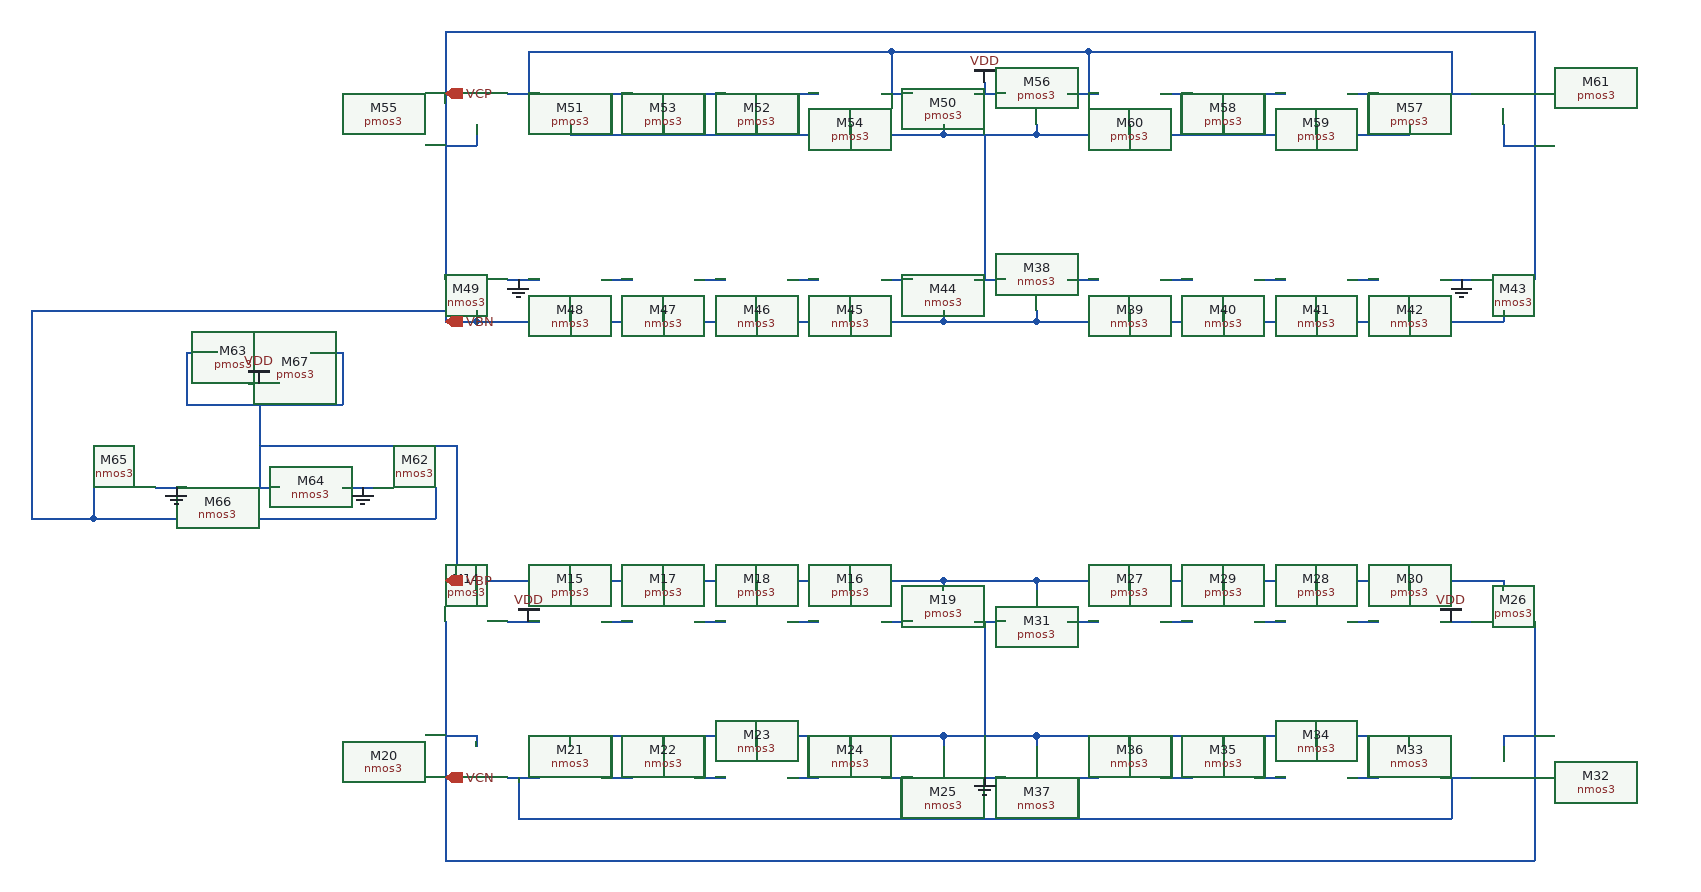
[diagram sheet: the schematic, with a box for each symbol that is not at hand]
v {xschem version=3.4.3 file_version=1.2
}
G {}
K {}
V {}
S {}
E {}
N 700 -140 730 -140 {
lab=VDD}
N 790 -140 820 -140 {
lab=#net1}
N 880 -140 910 -140 {
lab=#net2}
N 970 -140 1000 -140 {
lab=#net3}
N 1060 -140 1090 -140 {
lab=#net4}
N 760 -180 760 -170 {
lab=VBP}
N 850 -180 850 -170 {
lab=VBP}
N 940 -180 940 -170 {
lab=VBP}
N 670 -180 670 -170 {
lab=VBP}
N 1030 -180 1030 -170 {
lab=VBP}
N 1120 -180 1120 -170 {
lab=VBP}
N 640 -180 1120 -180 {
lab=VBP}
N 700 10 730 10 {
lab=#net5}
N 790 10 820 10 {
lab=#net6}
N 880 10 910 10 {
lab=#net6}
N 970 10 1000 10 {
lab=#net6}
N 1060 10 1090 10 {
lab=#net5}
N 670 -30 670 -20 {
lab=VCN}
N 760 -30 760 -20 {
lab=#net6}
N 850 -30 850 -20 {
lab=#net6}
N 940 -30 940 -20 {
lab=#net6}
N 1030 -30 1030 -20 {
lab=#net6}
N 1120 -30 1120 -20 {
lab=#net6}
N 760 -30 1120 -30 {
lab=#net6}
N 1600 -140 1630 -140 {
lab=VDD}
N 1510 -140 1540 -140 {
lab=#net7}
N 1420 -140 1450 -140 {
lab=#net8}
N 1330 -140 1360 -140 {
lab=#net9}
N 1240 -140 1270 -140 {
lab=#net10}
N 1570 -180 1570 -170 {
lab=VBP}
N 1480 -180 1480 -170 {
lab=VBP}
N 1390 -180 1390 -170 {
lab=VBP}
N 1660 -180 1660 -170 {
lab=VBP}
N 1300 -180 1300 -170 {
lab=VBP}
N 1210 -180 1210 -170 {
lab=VBP}
N 1600 10 1630 10 {
lab=#net5}
N 1510 10 1540 10 {
lab=#net6}
N 1420 10 1450 10 {
lab=#net6}
N 1330 10 1360 10 {
lab=#net6}
N 1240 10 1270 10 {
lab=#net5}
N 1660 -30 1660 -20 {
lab=VCN}
N 1570 -30 1570 -20 {
lab=#net6}
N 1480 -30 1480 -20 {
lab=#net6}
N 1390 -30 1390 -20 {
lab=#net6}
N 1300 -30 1300 -20 {
lab=#net6}
N 1210 -30 1210 -20 {
lab=#net6}
N 1210 -30 1570 -30 {
lab=#net6}
N 1150 10 1180 10 {
lab=GND}
N 1120 -30 1210 -30 {
lab=#net6}
N 1150 -140 1180 -140 {
lab=#net6}
N 640 -140 640 10 {
lab=VCN}
N 640 -30 670 -30 {
lab=VCN}
N 1690 -140 1690 10 {
lab=VCN}
N 1660 -30 1690 -30 {
lab=VCN}
N 1160 -140 1160 -30 {
lab=#net6}
N 710 10 710 50 {
lab=#net5}
N 710 50 900 50 {
lab=#net5}
N 900 50 1610 50 {
lab=#net5}
N 1610 10 1610 50 {
lab=#net5}
N 800 -30 800 10 {
lab=#net6}
N 890 -30 890 10 {
lab=#net6}
N 1080 10 1080 50 {
lab=#net5}
N 990 -30 990 10 {
lab=#net6}
N 1250 10 1250 50 {
lab=#net5}
N 1340 -30 1340 10 {
lab=#net6}
N 1430 -30 1430 10 {
lab=#net6}
N 1530 -30 1530 10 {
lab=#net6}
N 1210 -180 1660 -180 {
lab=VBP}
N 670 -440 670 -430 {
lab=VBN}
N 760 -440 760 -430 {
lab=VBN}
N 850 -440 850 -430 {
lab=VBN}
N 940 -440 940 -430 {
lab=VBN}
N 1030 -440 1030 -430 {
lab=VBN}
N 1120 -440 1120 -430 {
lab=VBN}
N 670 -430 1120 -430 {
lab=VBN}
N 700 -470 730 -470 {
lab=GND}
N 790 -470 820 -470 {
lab=#net11}
N 880 -470 910 -470 {
lab=#net12}
N 970 -470 1000 -470 {
lab=#net13}
N 1060 -470 1090 -470 {
lab=#net14}
N 700 -650 730 -650 {
lab=#net15}
N 790 -650 820 -650 {
lab=#net16}
N 880 -650 910 -650 {
lab=#net16}
N 970 -650 1000 -650 {
lab=#net16}
N 1060 -650 1090 -650 {
lab=#net15}
N 640 -650 640 -470 {
lab=VCP}
N 670 -620 670 -600 {
lab=VCP}
N 640 -600 670 -600 {
lab=VCP}
N 760 -620 760 -610 {
lab=#net16}
N 760 -610 1120 -610 {
lab=#net16}
N 1120 -620 1120 -610 {
lab=#net16}
N 800 -650 800 -610 {
lab=#net16}
N 720 -690 720 -650 {
lab=#net15}
N 720 -690 1070 -690 {
lab=#net15}
N 1070 -690 1070 -650 {
lab=#net15}
N 850 -620 850 -610 {
lab=#net16}
N 940 -620 940 -610 {
lab=#net16}
N 1030 -620 1030 -610 {
lab=#net16}
N 1160 -660 1160 -650 {
lab=VDD}
N 1660 -440 1660 -430 {
lab=VBN}
N 1570 -440 1570 -430 {
lab=VBN}
N 1480 -440 1480 -430 {
lab=VBN}
N 1390 -440 1390 -430 {
lab=VBN}
N 1300 -440 1300 -430 {
lab=VBN}
N 1210 -440 1210 -430 {
lab=VBN}
N 1210 -430 1660 -430 {
lab=VBN}
N 1600 -470 1630 -470 {
lab=GND}
N 1510 -470 1540 -470 {
lab=#net17}
N 1420 -470 1450 -470 {
lab=#net18}
N 1330 -470 1360 -470 {
lab=#net19}
N 1240 -470 1270 -470 {
lab=#net20}
N 1600 -650 1630 -650 {
lab=#net15}
N 1510 -650 1540 -650 {
lab=#net16}
N 1420 -650 1450 -650 {
lab=#net16}
N 1330 -650 1360 -650 {
lab=#net16}
N 1240 -650 1270 -650 {
lab=#net15}
N 1690 -650 1690 -470 {
lab=VCP}
N 1660 -620 1660 -600 {
lab=VCP}
N 1660 -600 1690 -600 {
lab=VCP}
N 1570 -620 1570 -610 {
lab=#net16}
N 1210 -610 1570 -610 {
lab=#net16}
N 1210 -620 1210 -610 {
lab=#net16}
N 1530 -650 1530 -610 {
lab=#net16}
N 1610 -690 1610 -650 {
lab=#net15}
N 1260 -690 1610 -690 {
lab=#net15}
N 1260 -690 1260 -650 {
lab=#net15}
N 1480 -620 1480 -610 {
lab=#net16}
N 1390 -620 1390 -610 {
lab=#net16}
N 1300 -620 1300 -610 {
lab=#net16}
N 1150 -650 1180 -650 {
lab=VDD}
N 1150 -470 1180 -470 {
lab=#net16}
N 1120 -610 1210 -610 {
lab=#net16}
N 1160 -610 1160 -470 {
lab=#net16}
N 1070 -690 1260 -690 {
lab=#net15}
N 1690 -710 1690 -650 {
lab=VCP}
N 640 -710 1690 -710 {
lab=VCP}
N 640 -710 640 -640 {
lab=VCP}
N 640 10 640 90 {
lab=VCN}
N 640 90 1690 90 {
lab=VCN}
N 1690 10 1690 90 {
lab=VCN}
N 640 -430 670 -430 {
lab=VBN}
N 630 -270 630 -240 {
lab=VBN}
N 510 -240 630 -240 {
lab=VBN}
N 540 -270 570 -270 {
lab=GND}
N 300 -270 300 -240 {
lab=VBN}
N 300 -240 420 -240 {
lab=VBN}
N 360 -270 390 -270 {
lab=GND}
N 450 -270 480 -270 {
lab=#net21}
N 420 -240 510 -240 {
lab=VBN}
N 450 -370 480 -370 {
lab=VDD}
N 390 -400 390 -370 {
lab=#net21}
N 390 -400 420 -400 {
lab=#net21}
N 510 -400 540 -400 {
lab=#net21}
N 540 -400 540 -370 {
lab=#net21}
N 390 -370 390 -350 {
lab=#net21}
N 390 -350 540 -350 {
lab=#net21}
N 540 -370 540 -350 {
lab=#net21}
N 460 -350 460 -270 {
lab=#net21}
N 1120 -430 1210 -430 {
lab=VBN}
N 1120 -180 1210 -180 {
lab=VBP}
N 890 -650 890 -610 {
lab=#net16}
N 980 -650 980 -610 {
lab=#net16}
N 1350 -650 1350 -610 {
lab=#net16}
N 1430 -650 1430 -610 {
lab=#net16}
N 460 -310 650 -310 {}
N 650 -310 650 -180 {}
N 240 -240 300 -240 {}
N 240 -440 240 -240 {}
N 240 -440 640 -440 {}
N 640 -440 640 -430 {}
C {madvlsi/pmos3.sym} 670 -140 1 0 {name=M14
L=0.5
W=12
body=VDD
nf=1
mult=1
ad="'int((nf+1)/2) * W/nf * 0.29'" 
pd="'2*int((nf+1)/2) * (W/nf + 0.29)'"
as="'int((nf+2)/2) * W/nf * 0.29'" 
ps="'2*int((nf+2)/2) * (W/nf + 0.29)'"
nrd="'0.29 / W'" nrs="'0.29 / W'"
sa=0 sb=0 sd=0
model=pfet_01v8
spiceprefix=X
}
C {madvlsi/pmos3.sym} 1030 -140 1 0 {name=M16
L=0.5
W=12
body=VDD
nf=1
mult=1
ad="'int((nf+1)/2) * W/nf * 0.29'" 
pd="'2*int((nf+1)/2) * (W/nf + 0.29)'"
as="'int((nf+2)/2) * W/nf * 0.29'" 
ps="'2*int((nf+2)/2) * (W/nf + 0.29)'"
nrd="'0.29 / W'" nrs="'0.29 / W'"
sa=0 sb=0 sd=0
model=pfet_01v8
spiceprefix=X
}
C {madvlsi/pmos3.sym} 850 -140 1 0 {name=M17
L=0.5
W=12
body=VDD
nf=1
mult=1
ad="'int((nf+1)/2) * W/nf * 0.29'" 
pd="'2*int((nf+1)/2) * (W/nf + 0.29)'"
as="'int((nf+2)/2) * W/nf * 0.29'" 
ps="'2*int((nf+2)/2) * (W/nf + 0.29)'"
nrd="'0.29 / W'" nrs="'0.29 / W'"
sa=0 sb=0 sd=0
model=pfet_01v8
spiceprefix=X
}
C {madvlsi/pmos3.sym} 940 -140 1 0 {name=M18
L=0.5
W=12
body=VDD
nf=1
mult=1
ad="'int((nf+1)/2) * W/nf * 0.29'" 
pd="'2*int((nf+1)/2) * (W/nf + 0.29)'"
as="'int((nf+2)/2) * W/nf * 0.29'" 
ps="'2*int((nf+2)/2) * (W/nf + 0.29)'"
nrd="'0.29 / W'" nrs="'0.29 / W'"
sa=0 sb=0 sd=0
model=pfet_01v8
spiceprefix=X
}
C {madvlsi/pmos3.sym} 760 -140 1 0 {name=M15
L=0.5
W=12
body=VDD
nf=1
mult=1
ad="'int((nf+1)/2) * W/nf * 0.29'" 
pd="'2*int((nf+1)/2) * (W/nf + 0.29)'"
as="'int((nf+2)/2) * W/nf * 0.29'" 
ps="'2*int((nf+2)/2) * (W/nf + 0.29)'"
nrd="'0.29 / W'" nrs="'0.29 / W'"
sa=0 sb=0 sd=0
model=pfet_01v8
spiceprefix=X
}
C {madvlsi/pmos3.sym} 1120 -140 1 0 {name=M19
L=0.5
W=12
body=VDD
nf=1
mult=1
ad="'int((nf+1)/2) * W/nf * 0.29'" 
pd="'2*int((nf+1)/2) * (W/nf + 0.29)'"
as="'int((nf+2)/2) * W/nf * 0.29'" 
ps="'2*int((nf+2)/2) * (W/nf + 0.29)'"
nrd="'0.29 / W'" nrs="'0.29 / W'"
sa=0 sb=0 sd=0
model=pfet_01v8
spiceprefix=X
}
C {madvlsi/vdd.sym} 720 -140 0 0 {name=l4 lab=VDD}
C {madvlsi/nmos3.sym} 670 10 3 1 {name=M20
L=0.5
W=12
body=GND
nf=1
mult=1
ad="'int((nf+1)/2) * W/nf * 0.29'" 
pd="'2*int((nf+1)/2) * (W/nf + 0.29)'"
as="'int((nf+2)/2) * W/nf * 0.29'" 
ps="'2*int((nf+2)/2) * (W/nf + 0.29)'"
nrd="'0.29 / W'" nrs="'0.29 / W'"
sa=0 sb=0 sd=0
model=nfet_01v8
spiceprefix=X
}
C {madvlsi/nmos3.sym} 760 10 3 1 {name=M21
L=0.5
W=12
body=GND
nf=1
mult=1
ad="'int((nf+1)/2) * W/nf * 0.29'" 
pd="'2*int((nf+1)/2) * (W/nf + 0.29)'"
as="'int((nf+2)/2) * W/nf * 0.29'" 
ps="'2*int((nf+2)/2) * (W/nf + 0.29)'"
nrd="'0.29 / W'" nrs="'0.29 / W'"
sa=0 sb=0 sd=0
model=nfet_01v8
spiceprefix=X
}
C {madvlsi/nmos3.sym} 850 10 3 1 {name=M22
L=0.5
W=12
body=GND
nf=1
mult=1
ad="'int((nf+1)/2) * W/nf * 0.29'" 
pd="'2*int((nf+1)/2) * (W/nf + 0.29)'"
as="'int((nf+2)/2) * W/nf * 0.29'" 
ps="'2*int((nf+2)/2) * (W/nf + 0.29)'"
nrd="'0.29 / W'" nrs="'0.29 / W'"
sa=0 sb=0 sd=0
model=nfet_01v8
spiceprefix=X
}
C {madvlsi/nmos3.sym} 940 10 3 1 {name=M23
L=0.5
W=12
body=GND
nf=1
mult=1
ad="'int((nf+1)/2) * W/nf * 0.29'" 
pd="'2*int((nf+1)/2) * (W/nf + 0.29)'"
as="'int((nf+2)/2) * W/nf * 0.29'" 
ps="'2*int((nf+2)/2) * (W/nf + 0.29)'"
nrd="'0.29 / W'" nrs="'0.29 / W'"
sa=0 sb=0 sd=0
model=nfet_01v8
spiceprefix=X
}
C {madvlsi/nmos3.sym} 1030 10 3 1 {name=M24
L=0.5
W=12
body=GND
nf=1
mult=1
ad="'int((nf+1)/2) * W/nf * 0.29'" 
pd="'2*int((nf+1)/2) * (W/nf + 0.29)'"
as="'int((nf+2)/2) * W/nf * 0.29'" 
ps="'2*int((nf+2)/2) * (W/nf + 0.29)'"
nrd="'0.29 / W'" nrs="'0.29 / W'"
sa=0 sb=0 sd=0
model=nfet_01v8
spiceprefix=X
}
C {madvlsi/nmos3.sym} 1120 10 3 1 {name=M25
L=0.5
W=12
body=GND
nf=1
mult=1
ad="'int((nf+1)/2) * W/nf * 0.29'" 
pd="'2*int((nf+1)/2) * (W/nf + 0.29)'"
as="'int((nf+2)/2) * W/nf * 0.29'" 
ps="'2*int((nf+2)/2) * (W/nf + 0.29)'"
nrd="'0.29 / W'" nrs="'0.29 / W'"
sa=0 sb=0 sd=0
model=nfet_01v8
spiceprefix=X
}
C {madvlsi/pmos3.sym} 1660 -140 3 1 {name=M26
L=0.5
W=12
body=VDD
nf=1
mult=1
ad="'int((nf+1)/2) * W/nf * 0.29'" 
pd="'2*int((nf+1)/2) * (W/nf + 0.29)'"
as="'int((nf+2)/2) * W/nf * 0.29'" 
ps="'2*int((nf+2)/2) * (W/nf + 0.29)'"
nrd="'0.29 / W'" nrs="'0.29 / W'"
sa=0 sb=0 sd=0
model=pfet_01v8
spiceprefix=X
}
C {madvlsi/pmos3.sym} 1300 -140 3 1 {name=M27
L=0.5
W=12
body=VDD
nf=1
mult=1
ad="'int((nf+1)/2) * W/nf * 0.29'" 
pd="'2*int((nf+1)/2) * (W/nf + 0.29)'"
as="'int((nf+2)/2) * W/nf * 0.29'" 
ps="'2*int((nf+2)/2) * (W/nf + 0.29)'"
nrd="'0.29 / W'" nrs="'0.29 / W'"
sa=0 sb=0 sd=0
model=pfet_01v8
spiceprefix=X
}
C {madvlsi/pmos3.sym} 1480 -140 3 1 {name=M28
L=0.5
W=12
body=VDD
nf=1
mult=1
ad="'int((nf+1)/2) * W/nf * 0.29'" 
pd="'2*int((nf+1)/2) * (W/nf + 0.29)'"
as="'int((nf+2)/2) * W/nf * 0.29'" 
ps="'2*int((nf+2)/2) * (W/nf + 0.29)'"
nrd="'0.29 / W'" nrs="'0.29 / W'"
sa=0 sb=0 sd=0
model=pfet_01v8
spiceprefix=X
}
C {madvlsi/pmos3.sym} 1390 -140 3 1 {name=M29
L=0.5
W=12
body=VDD
nf=1
mult=1
ad="'int((nf+1)/2) * W/nf * 0.29'" 
pd="'2*int((nf+1)/2) * (W/nf + 0.29)'"
as="'int((nf+2)/2) * W/nf * 0.29'" 
ps="'2*int((nf+2)/2) * (W/nf + 0.29)'"
nrd="'0.29 / W'" nrs="'0.29 / W'"
sa=0 sb=0 sd=0
model=pfet_01v8
spiceprefix=X
}
C {madvlsi/pmos3.sym} 1570 -140 3 1 {name=M30
L=0.5
W=12
body=VDD
nf=1
mult=1
ad="'int((nf+1)/2) * W/nf * 0.29'" 
pd="'2*int((nf+1)/2) * (W/nf + 0.29)'"
as="'int((nf+2)/2) * W/nf * 0.29'" 
ps="'2*int((nf+2)/2) * (W/nf + 0.29)'"
nrd="'0.29 / W'" nrs="'0.29 / W'"
sa=0 sb=0 sd=0
model=pfet_01v8
spiceprefix=X
}
C {madvlsi/pmos3.sym} 1210 -140 3 1 {name=M31
L=0.5
W=12
body=VDD
nf=1
mult=1
ad="'int((nf+1)/2) * W/nf * 0.29'" 
pd="'2*int((nf+1)/2) * (W/nf + 0.29)'"
as="'int((nf+2)/2) * W/nf * 0.29'" 
ps="'2*int((nf+2)/2) * (W/nf + 0.29)'"
nrd="'0.29 / W'" nrs="'0.29 / W'"
sa=0 sb=0 sd=0
model=pfet_01v8
spiceprefix=X
}
C {madvlsi/vdd.sym} 1610 -140 0 1 {name=l5 lab=VDD}
C {madvlsi/nmos3.sym} 1660 10 1 0 {name=M32
L=0.5
W=12
body=GND
nf=1
mult=1
ad="'int((nf+1)/2) * W/nf * 0.29'" 
pd="'2*int((nf+1)/2) * (W/nf + 0.29)'"
as="'int((nf+2)/2) * W/nf * 0.29'" 
ps="'2*int((nf+2)/2) * (W/nf + 0.29)'"
nrd="'0.29 / W'" nrs="'0.29 / W'"
sa=0 sb=0 sd=0
model=nfet_01v8
spiceprefix=X
}
C {madvlsi/nmos3.sym} 1570 10 1 0 {name=M33
L=0.5
W=12
body=GND
nf=1
mult=1
ad="'int((nf+1)/2) * W/nf * 0.29'" 
pd="'2*int((nf+1)/2) * (W/nf + 0.29)'"
as="'int((nf+2)/2) * W/nf * 0.29'" 
ps="'2*int((nf+2)/2) * (W/nf + 0.29)'"
nrd="'0.29 / W'" nrs="'0.29 / W'"
sa=0 sb=0 sd=0
model=nfet_01v8
spiceprefix=X
}
C {madvlsi/nmos3.sym} 1480 10 1 0 {name=M34
L=0.5
W=12
body=GND
nf=1
mult=1
ad="'int((nf+1)/2) * W/nf * 0.29'" 
pd="'2*int((nf+1)/2) * (W/nf + 0.29)'"
as="'int((nf+2)/2) * W/nf * 0.29'" 
ps="'2*int((nf+2)/2) * (W/nf + 0.29)'"
nrd="'0.29 / W'" nrs="'0.29 / W'"
sa=0 sb=0 sd=0
model=nfet_01v8
spiceprefix=X
}
C {madvlsi/nmos3.sym} 1390 10 1 0 {name=M35
L=0.5
W=12
body=GND
nf=1
mult=1
ad="'int((nf+1)/2) * W/nf * 0.29'" 
pd="'2*int((nf+1)/2) * (W/nf + 0.29)'"
as="'int((nf+2)/2) * W/nf * 0.29'" 
ps="'2*int((nf+2)/2) * (W/nf + 0.29)'"
nrd="'0.29 / W'" nrs="'0.29 / W'"
sa=0 sb=0 sd=0
model=nfet_01v8
spiceprefix=X
}
C {madvlsi/nmos3.sym} 1300 10 1 0 {name=M36
L=0.5
W=12
body=GND
nf=1
mult=1
ad="'int((nf+1)/2) * W/nf * 0.29'" 
pd="'2*int((nf+1)/2) * (W/nf + 0.29)'"
as="'int((nf+2)/2) * W/nf * 0.29'" 
ps="'2*int((nf+2)/2) * (W/nf + 0.29)'"
nrd="'0.29 / W'" nrs="'0.29 / W'"
sa=0 sb=0 sd=0
model=nfet_01v8
spiceprefix=X
}
C {madvlsi/nmos3.sym} 1210 10 1 0 {name=M37
L=0.5
W=12
body=GND
nf=1
mult=1
ad="'int((nf+1)/2) * W/nf * 0.29'" 
pd="'2*int((nf+1)/2) * (W/nf + 0.29)'"
as="'int((nf+2)/2) * W/nf * 0.29'" 
ps="'2*int((nf+2)/2) * (W/nf + 0.29)'"
nrd="'0.29 / W'" nrs="'0.29 / W'"
sa=0 sb=0 sd=0
model=nfet_01v8
spiceprefix=X
}
C {devices/opin.sym} 640 -180 2 0 {name=p2 lab=VBP}
C {devices/opin.sym} 640 10 2 0 {name=p6 lab=VCN}
C {madvlsi/gnd.sym} 1160 10 0 0 {name=l6 lab=GND}
C {madvlsi/nmos3.sym} 1120 -470 3 0 {name=M44
L=0.5
W=12
body=GND
nf=1
mult=1
ad="'int((nf+1)/2) * W/nf * 0.29'" 
pd="'2*int((nf+1)/2) * (W/nf + 0.29)'"
as="'int((nf+2)/2) * W/nf * 0.29'" 
ps="'2*int((nf+2)/2) * (W/nf + 0.29)'"
nrd="'0.29 / W'" nrs="'0.29 / W'"
sa=0 sb=0 sd=0
model=nfet_01v8
spiceprefix=X
}
C {madvlsi/nmos3.sym} 1030 -470 3 0 {name=M45
L=0.5
W=12
body=GND
nf=1
mult=1
ad="'int((nf+1)/2) * W/nf * 0.29'" 
pd="'2*int((nf+1)/2) * (W/nf + 0.29)'"
as="'int((nf+2)/2) * W/nf * 0.29'" 
ps="'2*int((nf+2)/2) * (W/nf + 0.29)'"
nrd="'0.29 / W'" nrs="'0.29 / W'"
sa=0 sb=0 sd=0
model=nfet_01v8
spiceprefix=X
}
C {madvlsi/nmos3.sym} 940 -470 3 0 {name=M46
L=0.5
W=12
body=GND
nf=1
mult=1
ad="'int((nf+1)/2) * W/nf * 0.29'" 
pd="'2*int((nf+1)/2) * (W/nf + 0.29)'"
as="'int((nf+2)/2) * W/nf * 0.29'" 
ps="'2*int((nf+2)/2) * (W/nf + 0.29)'"
nrd="'0.29 / W'" nrs="'0.29 / W'"
sa=0 sb=0 sd=0
model=nfet_01v8
spiceprefix=X
}
C {madvlsi/nmos3.sym} 850 -470 3 0 {name=M47
L=0.5
W=12
body=GND
nf=1
mult=1
ad="'int((nf+1)/2) * W/nf * 0.29'" 
pd="'2*int((nf+1)/2) * (W/nf + 0.29)'"
as="'int((nf+2)/2) * W/nf * 0.29'" 
ps="'2*int((nf+2)/2) * (W/nf + 0.29)'"
nrd="'0.29 / W'" nrs="'0.29 / W'"
sa=0 sb=0 sd=0
model=nfet_01v8
spiceprefix=X
}
C {madvlsi/nmos3.sym} 760 -470 3 0 {name=M48
L=0.5
W=12
body=GND
nf=1
mult=1
ad="'int((nf+1)/2) * W/nf * 0.29'" 
pd="'2*int((nf+1)/2) * (W/nf + 0.29)'"
as="'int((nf+2)/2) * W/nf * 0.29'" 
ps="'2*int((nf+2)/2) * (W/nf + 0.29)'"
nrd="'0.29 / W'" nrs="'0.29 / W'"
sa=0 sb=0 sd=0
model=nfet_01v8
spiceprefix=X
}
C {madvlsi/nmos3.sym} 670 -470 3 0 {name=M49
L=0.5
W=12
body=GND
nf=1
mult=1
ad="'int((nf+1)/2) * W/nf * 0.29'" 
pd="'2*int((nf+1)/2) * (W/nf + 0.29)'"
as="'int((nf+2)/2) * W/nf * 0.29'" 
ps="'2*int((nf+2)/2) * (W/nf + 0.29)'"
nrd="'0.29 / W'" nrs="'0.29 / W'"
sa=0 sb=0 sd=0
model=nfet_01v8
spiceprefix=X
}
C {madvlsi/pmos3.sym} 1120 -650 3 0 {name=M50
L=0.5
W=12
body=VDD
nf=1
mult=1
ad="'int((nf+1)/2) * W/nf * 0.29'" 
pd="'2*int((nf+1)/2) * (W/nf + 0.29)'"
as="'int((nf+2)/2) * W/nf * 0.29'" 
ps="'2*int((nf+2)/2) * (W/nf + 0.29)'"
nrd="'0.29 / W'" nrs="'0.29 / W'"
sa=0 sb=0 sd=0
model=pfet_01v8
spiceprefix=X
}
C {madvlsi/pmos3.sym} 760 -650 3 0 {name=M51
L=0.5
W=12
body=VDD
nf=1
mult=1
ad="'int((nf+1)/2) * W/nf * 0.29'" 
pd="'2*int((nf+1)/2) * (W/nf + 0.29)'"
as="'int((nf+2)/2) * W/nf * 0.29'" 
ps="'2*int((nf+2)/2) * (W/nf + 0.29)'"
nrd="'0.29 / W'" nrs="'0.29 / W'"
sa=0 sb=0 sd=0
model=pfet_01v8
spiceprefix=X
}
C {madvlsi/pmos3.sym} 940 -650 3 0 {name=M52
L=0.5
W=12
body=VDD
nf=1
mult=1
ad="'int((nf+1)/2) * W/nf * 0.29'" 
pd="'2*int((nf+1)/2) * (W/nf + 0.29)'"
as="'int((nf+2)/2) * W/nf * 0.29'" 
ps="'2*int((nf+2)/2) * (W/nf + 0.29)'"
nrd="'0.29 / W'" nrs="'0.29 / W'"
sa=0 sb=0 sd=0
model=pfet_01v8
spiceprefix=X
}
C {madvlsi/pmos3.sym} 850 -650 3 0 {name=M53
L=0.5
W=12
body=VDD
nf=1
mult=1
ad="'int((nf+1)/2) * W/nf * 0.29'" 
pd="'2*int((nf+1)/2) * (W/nf + 0.29)'"
as="'int((nf+2)/2) * W/nf * 0.29'" 
ps="'2*int((nf+2)/2) * (W/nf + 0.29)'"
nrd="'0.29 / W'" nrs="'0.29 / W'"
sa=0 sb=0 sd=0
model=pfet_01v8
spiceprefix=X
}
C {madvlsi/pmos3.sym} 1030 -650 3 0 {name=M54
L=0.5
W=12
body=VDD
nf=1
mult=1
ad="'int((nf+1)/2) * W/nf * 0.29'" 
pd="'2*int((nf+1)/2) * (W/nf + 0.29)'"
as="'int((nf+2)/2) * W/nf * 0.29'" 
ps="'2*int((nf+2)/2) * (W/nf + 0.29)'"
nrd="'0.29 / W'" nrs="'0.29 / W'"
sa=0 sb=0 sd=0
model=pfet_01v8
spiceprefix=X
}
C {madvlsi/pmos3.sym} 670 -650 3 0 {name=M55
L=0.5
W=12
body=VDD
nf=1
mult=1
ad="'int((nf+1)/2) * W/nf * 0.29'" 
pd="'2*int((nf+1)/2) * (W/nf + 0.29)'"
as="'int((nf+2)/2) * W/nf * 0.29'" 
ps="'2*int((nf+2)/2) * (W/nf + 0.29)'"
nrd="'0.29 / W'" nrs="'0.29 / W'"
sa=0 sb=0 sd=0
model=pfet_01v8
spiceprefix=X
}
C {madvlsi/gnd.sym} 710 -470 0 0 {name=l8 lab=GND}
C {madvlsi/vdd.sym} 1160 -660 0 1 {name=l9 lab=VDD}
C {madvlsi/nmos3.sym} 1210 -470 1 1 {name=M38
L=0.5
W=12
body=GND
nf=1
mult=1
ad="'int((nf+1)/2) * W/nf * 0.29'" 
pd="'2*int((nf+1)/2) * (W/nf + 0.29)'"
as="'int((nf+2)/2) * W/nf * 0.29'" 
ps="'2*int((nf+2)/2) * (W/nf + 0.29)'"
nrd="'0.29 / W'" nrs="'0.29 / W'"
sa=0 sb=0 sd=0
model=nfet_01v8
spiceprefix=X
}
C {madvlsi/nmos3.sym} 1300 -470 1 1 {name=M39
L=0.5
W=12
body=GND
nf=1
mult=1
ad="'int((nf+1)/2) * W/nf * 0.29'" 
pd="'2*int((nf+1)/2) * (W/nf + 0.29)'"
as="'int((nf+2)/2) * W/nf * 0.29'" 
ps="'2*int((nf+2)/2) * (W/nf + 0.29)'"
nrd="'0.29 / W'" nrs="'0.29 / W'"
sa=0 sb=0 sd=0
model=nfet_01v8
spiceprefix=X
}
C {madvlsi/nmos3.sym} 1390 -470 1 1 {name=M40
L=0.5
W=12
body=GND
nf=1
mult=1
ad="'int((nf+1)/2) * W/nf * 0.29'" 
pd="'2*int((nf+1)/2) * (W/nf + 0.29)'"
as="'int((nf+2)/2) * W/nf * 0.29'" 
ps="'2*int((nf+2)/2) * (W/nf + 0.29)'"
nrd="'0.29 / W'" nrs="'0.29 / W'"
sa=0 sb=0 sd=0
model=nfet_01v8
spiceprefix=X
}
C {madvlsi/nmos3.sym} 1480 -470 1 1 {name=M41
L=0.5
W=12
body=GND
nf=1
mult=1
ad="'int((nf+1)/2) * W/nf * 0.29'" 
pd="'2*int((nf+1)/2) * (W/nf + 0.29)'"
as="'int((nf+2)/2) * W/nf * 0.29'" 
ps="'2*int((nf+2)/2) * (W/nf + 0.29)'"
nrd="'0.29 / W'" nrs="'0.29 / W'"
sa=0 sb=0 sd=0
model=nfet_01v8
spiceprefix=X
}
C {madvlsi/nmos3.sym} 1570 -470 1 1 {name=M42
L=0.5
W=12
body=GND
nf=1
mult=1
ad="'int((nf+1)/2) * W/nf * 0.29'" 
pd="'2*int((nf+1)/2) * (W/nf + 0.29)'"
as="'int((nf+2)/2) * W/nf * 0.29'" 
ps="'2*int((nf+2)/2) * (W/nf + 0.29)'"
nrd="'0.29 / W'" nrs="'0.29 / W'"
sa=0 sb=0 sd=0
model=nfet_01v8
spiceprefix=X
}
C {madvlsi/nmos3.sym} 1660 -470 1 1 {name=M43
L=0.5
W=12
body=GND
nf=1
mult=1
ad="'int((nf+1)/2) * W/nf * 0.29'" 
pd="'2*int((nf+1)/2) * (W/nf + 0.29)'"
as="'int((nf+2)/2) * W/nf * 0.29'" 
ps="'2*int((nf+2)/2) * (W/nf + 0.29)'"
nrd="'0.29 / W'" nrs="'0.29 / W'"
sa=0 sb=0 sd=0
model=nfet_01v8
spiceprefix=X
}
C {madvlsi/pmos3.sym} 1210 -650 1 1 {name=M56
L=0.5
W=12
body=VDD
nf=1
mult=1
ad="'int((nf+1)/2) * W/nf * 0.29'" 
pd="'2*int((nf+1)/2) * (W/nf + 0.29)'"
as="'int((nf+2)/2) * W/nf * 0.29'" 
ps="'2*int((nf+2)/2) * (W/nf + 0.29)'"
nrd="'0.29 / W'" nrs="'0.29 / W'"
sa=0 sb=0 sd=0
model=pfet_01v8
spiceprefix=X
}
C {madvlsi/pmos3.sym} 1570 -650 1 1 {name=M57
L=0.5
W=12
body=VDD
nf=1
mult=1
ad="'int((nf+1)/2) * W/nf * 0.29'" 
pd="'2*int((nf+1)/2) * (W/nf + 0.29)'"
as="'int((nf+2)/2) * W/nf * 0.29'" 
ps="'2*int((nf+2)/2) * (W/nf + 0.29)'"
nrd="'0.29 / W'" nrs="'0.29 / W'"
sa=0 sb=0 sd=0
model=pfet_01v8
spiceprefix=X
}
C {madvlsi/pmos3.sym} 1390 -650 1 1 {name=M58
L=0.5
W=12
body=VDD
nf=1
mult=1
ad="'int((nf+1)/2) * W/nf * 0.29'" 
pd="'2*int((nf+1)/2) * (W/nf + 0.29)'"
as="'int((nf+2)/2) * W/nf * 0.29'" 
ps="'2*int((nf+2)/2) * (W/nf + 0.29)'"
nrd="'0.29 / W'" nrs="'0.29 / W'"
sa=0 sb=0 sd=0
model=pfet_01v8
spiceprefix=X
}
C {madvlsi/pmos3.sym} 1480 -650 1 1 {name=M59
L=0.5
W=12
body=VDD
nf=1
mult=1
ad="'int((nf+1)/2) * W/nf * 0.29'" 
pd="'2*int((nf+1)/2) * (W/nf + 0.29)'"
as="'int((nf+2)/2) * W/nf * 0.29'" 
ps="'2*int((nf+2)/2) * (W/nf + 0.29)'"
nrd="'0.29 / W'" nrs="'0.29 / W'"
sa=0 sb=0 sd=0
model=pfet_01v8
spiceprefix=X
}
C {madvlsi/pmos3.sym} 1300 -650 1 1 {name=M60
L=0.5
W=12
body=VDD
nf=1
mult=1
ad="'int((nf+1)/2) * W/nf * 0.29'" 
pd="'2*int((nf+1)/2) * (W/nf + 0.29)'"
as="'int((nf+2)/2) * W/nf * 0.29'" 
ps="'2*int((nf+2)/2) * (W/nf + 0.29)'"
nrd="'0.29 / W'" nrs="'0.29 / W'"
sa=0 sb=0 sd=0
model=pfet_01v8
spiceprefix=X
}
C {madvlsi/pmos3.sym} 1660 -650 1 1 {name=M61
L=0.5
W=12
body=VDD
nf=1
mult=1
ad="'int((nf+1)/2) * W/nf * 0.29'" 
pd="'2*int((nf+1)/2) * (W/nf + 0.29)'"
as="'int((nf+2)/2) * W/nf * 0.29'" 
ps="'2*int((nf+2)/2) * (W/nf + 0.29)'"
nrd="'0.29 / W'" nrs="'0.29 / W'"
sa=0 sb=0 sd=0
model=pfet_01v8
spiceprefix=X
}
C {madvlsi/gnd.sym} 1620 -470 0 1 {name=l10 lab=GND}
C {devices/opin.sym} 640 -650 2 0 {name=p7 lab=VCP}
C {devices/opin.sym} 640 -430 2 0 {name=p8 lab=VBN}
C {madvlsi/nmos3.sym} 600 -270 1 1 {name=M62
L=0.5
W=12
body=GND
nf=1
mult=1
ad="'int((nf+1)/2) * W/nf * 0.29'" 
pd="'2*int((nf+1)/2) * (W/nf + 0.29)'"
as="'int((nf+2)/2) * W/nf * 0.29'" 
ps="'2*int((nf+2)/2) * (W/nf + 0.29)'"
nrd="'0.29 / W'" nrs="'0.29 / W'"
sa=0 sb=0 sd=0
model=nfet_01v8
spiceprefix=X
}
C {madvlsi/nmos3.sym} 510 -270 3 0 {name=M64
L=0.5
W=12
body=GND
nf=1
mult=1
ad="'int((nf+1)/2) * W/nf * 0.29'" 
pd="'2*int((nf+1)/2) * (W/nf + 0.29)'"
as="'int((nf+2)/2) * W/nf * 0.29'" 
ps="'2*int((nf+2)/2) * (W/nf + 0.29)'"
nrd="'0.29 / W'" nrs="'0.29 / W'"
sa=0 sb=0 sd=0
model=nfet_01v8
spiceprefix=X
}
C {madvlsi/nmos3.sym} 330 -270 3 0 {name=M65
L=0.5
W=12
body=GND
nf=1
mult=1
ad="'int((nf+1)/2) * W/nf * 0.29'" 
pd="'2*int((nf+1)/2) * (W/nf + 0.29)'"
as="'int((nf+2)/2) * W/nf * 0.29'" 
ps="'2*int((nf+2)/2) * (W/nf + 0.29)'"
nrd="'0.29 / W'" nrs="'0.29 / W'"
sa=0 sb=0 sd=0
model=nfet_01v8
spiceprefix=X
}
C {madvlsi/nmos3.sym} 420 -270 1 1 {name=M66
L=0.5
W=12
body=GND
nf=1
mult=1
ad="'int((nf+1)/2) * W/nf * 0.29'" 
pd="'2*int((nf+1)/2) * (W/nf + 0.29)'"
as="'int((nf+2)/2) * W/nf * 0.29'" 
ps="'2*int((nf+2)/2) * (W/nf + 0.29)'"
nrd="'0.29 / W'" nrs="'0.29 / W'"
sa=0 sb=0 sd=0
model=nfet_01v8
spiceprefix=X
}
C {madvlsi/pmos3.sym} 420 -370 1 0 {name=M63
L=0.5
W=12
body=VDD
nf=1
mult=1
ad="'int((nf+1)/2) * W/nf * 0.29'" 
pd="'2*int((nf+1)/2) * (W/nf + 0.29)'"
as="'int((nf+2)/2) * W/nf * 0.29'" 
ps="'2*int((nf+2)/2) * (W/nf + 0.29)'"
nrd="'0.29 / W'" nrs="'0.29 / W'"
sa=0 sb=0 sd=0
model=pfet_01v8
spiceprefix=X
}
C {madvlsi/pmos3.sym} 510 -370 1 0 {name=M67
L=0.5
W=12
body=VDD
nf=1
mult=1
ad="'int((nf+1)/2) * W/nf * 0.29'" 
pd="'2*int((nf+1)/2) * (W/nf + 0.29)'"
as="'int((nf+2)/2) * W/nf * 0.29'" 
ps="'2*int((nf+2)/2) * (W/nf + 0.29)'"
nrd="'0.29 / W'" nrs="'0.29 / W'"
sa=0 sb=0 sd=0
model=pfet_01v8
spiceprefix=X
}
C {madvlsi/vdd.sym} 460 -370 0 0 {name=l12 lab=VDD}
C {madvlsi/gnd.sym} 380 -270 0 1 {name=l11 lab=GND}
C {madvlsi/gnd.sym} 560 -270 0 1 {name=l13 lab=GND}
